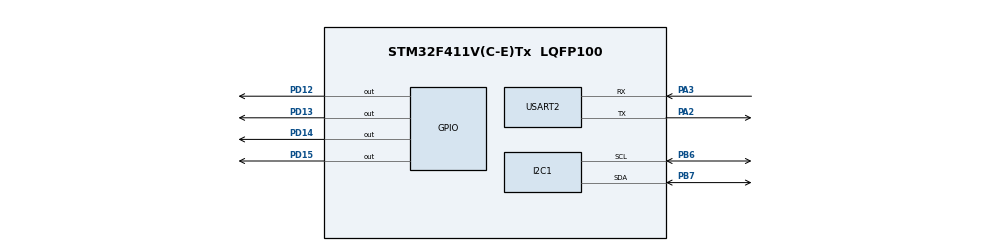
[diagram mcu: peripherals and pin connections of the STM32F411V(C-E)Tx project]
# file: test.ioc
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Mcu.Family=STM32F4
Mcu.Name=STM32F411V(C-E)Tx
Mcu.Package=LQFP100
NVIC.PriorityGroup=NVIC_PRIORITYGROUP_4
PA13.Mode=Serial_Wire
PA13.Signal=SYS_JTMS-SWDIO
PA14.Mode=Serial_Wire
PA14.Signal=SYS_JTCK-SWCLK
PA2.Mode=Asynchronous
PA2.Signal=USART2_TX
PA3.Mode=Asynchronous
PA3.Signal=USART2_RX
PB6.Mode=I2C
PB6.Signal=I2C1_SCL
PB7.Mode=I2C
PB7.Signal=I2C1_SDA
PD12.Signal=GPIO_Output
PD13.Signal=GPIO_Output
PD14.Signal=GPIO_Output
PD15.Signal=GPIO_Output
PH0\ -\ OSC_IN.Mode=HSE-External-Oscillator
PH0\ -\ OSC_IN.Signal=RCC_OSC_IN
PH1\ -\ OSC_OUT.Mode=HSE-External-Oscillator
PH1\ -\ OSC_OUT.Signal=RCC_OSC_OUT
ProjectManager.HeapSize=0x200
ProjectManager.StackSize=0x400
ProjectManager.TargetToolchain=STM32CubeIDE
RCC.48MHZClocksFreq_Value=48000000
RCC.AHBFreq_Value=96000000
RCC.APB1CLKDivider=RCC_HCLK_DIV2
RCC.APB1Freq_Value=48000000
RCC.APB1TimFreq_Value=96000000
RCC.APB2Freq_Value=96000000
RCC.APB2TimFreq_Value=96000000
RCC.CortexFreq_Value=96000000
RCC.HCLKFreq_Value=96000000
RCC.HSE_VALUE=8000000
RCC.HSI_VALUE=16000000
RCC.LSE_VALUE=32768
RCC.PLLM=4
RCC.PLLN=96
RCC.PLLSourceVirtual=RCC_PLLSOURCE_HSE
RCC.SYSCLKFreq_VALUE=96000000
RCC.SYSCLKSource=RCC_SYSCLKSOURCE_PLLCLK
RCC.VCOOutputFreq_Value=192000000
USART2.VirtualMode=VM_ASYNC
board=custom

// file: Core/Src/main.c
/* USER CODE BEGIN Header */
/**
  ******************************************************************************
  * @file           : main.c
  * @brief          : Main program body
  ******************************************************************************
  * @attention
  *
  * Copyright (c) 2023 STMicroelectronics.
  * All rights reserved.
  *
  * This software is licensed under terms that can be found in the LICENSE file
  * in the root directory of this software component.
  * If no LICENSE file comes with this software, it is provided AS-IS.
  *
  ******************************************************************************
  */
/* USER CODE END Header */
#include "main.h"
#include "math.h"
#include "string.h"
#include <stdbool.h>
#include "mpu6050.h"
#include "lcd.h"
#include "stdio.h"

I2C_HandleTypeDef hi2c1;

UART_HandleTypeDef huart2;

/* USER CODE BEGIN PV */
MPU6050_t MPU6050;
/* USER CODE END PV */

void SystemClock_Config(void);
static void MX_GPIO_Init(void);
static void MX_I2C1_Init(void);
static void MX_USART2_UART_Init(void);
/* USER CODE BEGIN PFP */

#define BMP180_ADDRESS 0xEE
#define atmPress 101325 //Pa
#define BMP180_I2C &hi2c1

float Ax=0,Ay=0,Az=0,Gx,Gy,Gz;
short AC1=0,AC2=0,AC3=0,B1=0,B2=0,MB=0,MC=0,MD=0;
unsigned short AC4=0,AC5=0,AC6=0;

//................../
long UT=0;
short oss=0;
long UP=0;
long X1=0,X2=0,X3=0,B3=0,B5=0;
unsigned long B4=0,B7=0;
long B6=0;
//'''''''''''''''''''''''''''''''''''''''''''''''''''''''''''
float temperature, pressure, altitude;

void read_calliberation_data (void)
{
	uint8_t Callib_Data[22] = {0};
	uint16_t Callib_Start = 0xAA;
	HAL_I2C_Mem_Read(BMP180_I2C, BMP180_ADDRESS, Callib_Start, 1, Callib_Data,22, HAL_MAX_DELAY);

	AC1 = ((Callib_Data[0] << 8) | Callib_Data[1]);
	AC2 = ((Callib_Data[2] << 8) | Callib_Data[3]);
	AC3 = ((Callib_Data[4] << 8) | Callib_Data[5]);
	AC4 = ((Callib_Data[6] << 8) | Callib_Data[7]);
	AC5 = ((Callib_Data[8] << 8) | Callib_Data[9]);
	AC6 = ((Callib_Data[10] << 8) | Callib_Data[11]);
	B1 = ((Callib_Data[12] << 8) | Callib_Data[13]);
	B2 = ((Callib_Data[14] << 8) | Callib_Data[15]);
	MB = ((Callib_Data[16] << 8) | Callib_Data[17]);
	MC = ((Callib_Data[18] << 8) | Callib_Data[19]);
	MD = ((Callib_Data[20] << 8) | Callib_Data[21]);
}

// Get uncompensated Temp
uint16_t Get_UTemp (void)
{
	uint8_t datatowrite = 0x2E;
	uint8_t Temp_RAW[2] = {0};
	HAL_I2C_Mem_Write(BMP180_I2C, BMP180_ADDRESS, 0xF4, 1, &datatowrite, 1, 1000);
	HAL_Delay (5);  // wait 4.5 ms
	HAL_I2C_Mem_Read(BMP180_I2C, BMP180_ADDRESS, 0xF6, 1, Temp_RAW, 2, 1000);
	return ((Temp_RAW[0]<<8) + Temp_RAW[1]);
}

float BMP180_GetTemp (void)
{
	long Temp=0;
	UT = Get_UTemp();
	X1 = ((UT-AC6) * (AC5/(pow(2,15))));
	X2 = ((MC*(pow(2,11))) / (X1+MD));
	B5 = X1+X2;
	Temp = (B5+8)/(pow(2,4));
	return Temp/10.0;
}

// Get uncompensated Pressure
uint32_t Get_UPress (int oss)   // oversampling setting 0,1,2,3
{
	uint8_t datatowrite = 0x34+(oss<<6);
	uint8_t Press_RAW[3] = {0};
	HAL_I2C_Mem_Write(BMP180_I2C, BMP180_ADDRESS, 0xF4, 1, &datatowrite, 1, 1000);
	switch (oss)
	{
		case (0):
			HAL_Delay (5);
			break;
		case (1):
			HAL_Delay (8);
			break;
		case (2):
			HAL_Delay (14);
			break;
		case (3):
			HAL_Delay (26);
			break;
	}
	HAL_I2C_Mem_Read(BMP180_I2C, BMP180_ADDRESS, 0xF6, 1, Press_RAW, 3, 1000);
	return (((Press_RAW[0]<<16)+(Press_RAW[1]<<8)+Press_RAW[2]) >> (8-oss));
}

float BMP180_GetPress (int oss)
{
	long Press = 0;
	UP = Get_UPress(oss);
	X1 = ((UT-AC6) * (AC5/(pow(2,15))));
	X2 = ((MC*(pow(2,11))) / (X1+MD));
	B5 = X1+X2;
	B6 = B5-4000;
	X1 = (B2 * (B6*B6/(pow(2,12))))/(pow(2,11));
	X2 = AC2*B6/(pow(2,11));
	X3 = X1+X2;
	B3 = (((AC1*4+X3)<<oss)+2)/4;
	X1 = AC3*B6/pow(2,13);
	X2 = (B1 * (B6*B6/(pow(2,12))))/(pow(2,16));
	X3 = ((X1+X2)+2)/pow(2,2);
	B4 = AC4*(unsigned long)(X3+32768)/(pow(2,15));
	B7 = ((unsigned long)UP-B3)*(50000>>oss);
	if (B7<0x80000000) Press = (B7*2)/B4;
	else Press = (B7/B4)*2;
	X1 = (Press/(pow(2,8)))*(Press/(pow(2,8)));
	X1 = (X1*3038)/(pow(2,16));
	X2 = (-7357*Press)/(pow(2,16));
	Press = Press + (X1+X2+3791)/(pow(2,4));

	return Press;
}

float BMP180_GetAlt (int oss)
{
	float Press;
	Press = BMP180_GetPress (oss);
	return 44330*(1-(pow(((float)Press/(float)atmPress), 0.19029495718)));
}

/* USER CODE END PFP */

int main(void)
{
  /* USER CODE BEGIN 1 */
char buf[4];
  /* USER CODE END 1 */

  /* MCU Configuration--------------------------------------------------------*/

  /* Reset of all peripherals, Initializes the Flash interface and the Systick. */
  HAL_Init();

  /* Configure the system clock */
  SystemClock_Config();

  /* Initialize all configured peripherals */
  MX_GPIO_Init();
  MX_I2C1_Init();
  MX_USART2_UART_Init();
  lcd_init();
  lcd_clear();
  /* USER CODE BEGIN 2 */
  while (MPU6050_Init(&hi2c1) == 1);
  /* USER CODE END 2 */

  /* Infinite loop */
  /* USER CODE BEGIN WHILE */
  while (1)
  {
	  MPU6050_Read_All(&hi2c1, &MPU6050);
	 	  HAL_Delay (100);

		  lcd_send_cmd (0x80|0x00);  // goto 1,1
		  lcd_send_string ("Ax=");
		  sprintf (buf, "%.2f", MPU6050.KalmanAngleX);
		  lcd_send_string (&buf);
		 // lcd_send_string ("g ");

		  lcd_send_cmd (0x80|0x40);  // goto 2,1
		  lcd_send_string ("Ay=");
		  sprintf (buf, "%.2f", MPU6050.KalmanAngleY);
		  lcd_send_string (buf);
		  //lcd_send_string ("g ");

		  lcd_send_cmd (0x80|0x09);  // goto 3,1
		  lcd_send_string ("Az=");
		  sprintf (buf, "%.2f", MPU6050.AngleZ);
		  lcd_send_string (buf);
		 // lcd_send_string ("g ");

		 //lcd_send_cmd (0x80|0x06);  // goto 1,11
		  //lcd_send_string ("Gx=");
		  //sprintf (buf, "%.2f", MPU6050.Gx);
		  //lcd_send_string (buf);

		  //lcd_send_string ("Gy=");
		  //sprintf (buf, "%.2f", MPU6050.Gy);
		 // lcd_send_string (buf);

//		  lcd_send_cmd (0x80|0x4B);  // goto 3,11
//		  lcd_send_string ("Gz=");
//		  sprintf (buf, "%.2f", MPU6050.Gz);
//		  lcd_send_string (buf);

		  HAL_Delay (250);  // wait for a while
	     /* USER CODE END WHILE */

  }
}

void SystemClock_Config(void)
{
  RCC_OscInitTypeDef RCC_OscInitStruct = {0};
  RCC_ClkInitTypeDef RCC_ClkInitStruct = {0};

  /** Configure the main internal regulator output voltage
  */
  __HAL_RCC_PWR_CLK_ENABLE();
  __HAL_PWR_VOLTAGESCALING_CONFIG(PWR_REGULATOR_VOLTAGE_SCALE1);

  /** Initializes the RCC Oscillators according to the specified parameters
  * in the RCC_OscInitTypeDef structure.
  */
  RCC_OscInitStruct.OscillatorType = RCC_OSCILLATORTYPE_HSE;
  RCC_OscInitStruct.HSEState = RCC_HSE_ON;
  RCC_OscInitStruct.PLL.PLLState = RCC_PLL_ON;
  RCC_OscInitStruct.PLL.PLLSource = RCC_PLLSOURCE_HSE;
  RCC_OscInitStruct.PLL.PLLM = 8;
  RCC_OscInitStruct.PLL.PLLN = 170;
  RCC_OscInitStruct.PLL.PLLP = RCC_PLLP_DIV2;
  RCC_OscInitStruct.PLL.PLLQ = 4;
  if (HAL_RCC_OscConfig(&RCC_OscInitStruct) != HAL_OK)
  {
    Error_Handler();
  }

  /** Initializes the CPU, AHB and APB buses clocks
  */
  RCC_ClkInitStruct.ClockType = RCC_CLOCKTYPE_HCLK|RCC_CLOCKTYPE_SYSCLK
                              |RCC_CLOCKTYPE_PCLK1|RCC_CLOCKTYPE_PCLK2;
  RCC_ClkInitStruct.SYSCLKSource = RCC_SYSCLKSOURCE_PLLCLK;
  RCC_ClkInitStruct.AHBCLKDivider = RCC_SYSCLK_DIV1;
  RCC_ClkInitStruct.APB1CLKDivider = RCC_HCLK_DIV2;
  RCC_ClkInitStruct.APB2CLKDivider = RCC_HCLK_DIV1;

  if (HAL_RCC_ClockConfig(&RCC_ClkInitStruct, FLASH_LATENCY_2) != HAL_OK)
  {
    Error_Handler();
  }
}

static void MX_I2C1_Init(void)
{

  hi2c1.Instance = I2C1;
  hi2c1.Init.ClockSpeed = 100000;
  hi2c1.Init.DutyCycle = I2C_DUTYCYCLE_2;
  hi2c1.Init.OwnAddress1 = 0;
  hi2c1.Init.AddressingMode = I2C_ADDRESSINGMODE_7BIT;
  hi2c1.Init.DualAddressMode = I2C_DUALADDRESS_DISABLE;
  hi2c1.Init.OwnAddress2 = 0;
  hi2c1.Init.GeneralCallMode = I2C_GENERALCALL_DISABLE;
  hi2c1.Init.NoStretchMode = I2C_NOSTRETCH_DISABLE;
  if (HAL_I2C_Init(&hi2c1) != HAL_OK)
  {
    Error_Handler();
  }

}

static void MX_USART2_UART_Init(void)
{

  huart2.Instance = USART2;
  huart2.Init.BaudRate = 115200;
  huart2.Init.WordLength = UART_WORDLENGTH_8B;
  huart2.Init.StopBits = UART_STOPBITS_1;
  huart2.Init.Parity = UART_PARITY_NONE;
  huart2.Init.Mode = UART_MODE_TX_RX;
  huart2.Init.HwFlowCtl = UART_HWCONTROL_NONE;
  huart2.Init.OverSampling = UART_OVERSAMPLING_16;
  if (HAL_UART_Init(&huart2) != HAL_OK)
  {
    Error_Handler();
  }

}

static void MX_GPIO_Init(void)
{
  GPIO_InitTypeDef GPIO_InitStruct = {0};

  /* GPIO Ports Clock Enable */
  __HAL_RCC_GPIOH_CLK_ENABLE();
  __HAL_RCC_GPIOA_CLK_ENABLE();
  __HAL_RCC_GPIOD_CLK_ENABLE();
  __HAL_RCC_GPIOB_CLK_ENABLE();

  /*Configure GPIO pin Output Level */
  HAL_GPIO_WritePin(GPIOD, GPIO_PIN_12|GPIO_PIN_13|GPIO_PIN_14|GPIO_PIN_15, GPIO_PIN_RESET);

  /*Configure GPIO pins : PD12 PD13 PD14 PD15 */
  GPIO_InitStruct.Pin = GPIO_PIN_12|GPIO_PIN_13|GPIO_PIN_14|GPIO_PIN_15;
  GPIO_InitStruct.Mode = GPIO_MODE_OUTPUT_PP;
  GPIO_InitStruct.Pull = GPIO_NOPULL;
  GPIO_InitStruct.Speed = GPIO_SPEED_FREQ_LOW;
  HAL_GPIO_Init(GPIOD, &GPIO_InitStruct);

}

void Error_Handler(void)
{
  __disable_irq();
  while (1)
  {
  }
}
